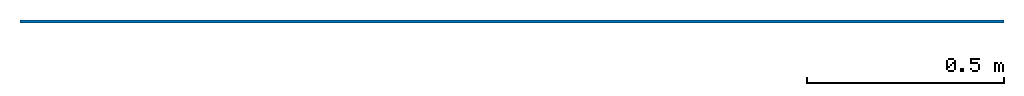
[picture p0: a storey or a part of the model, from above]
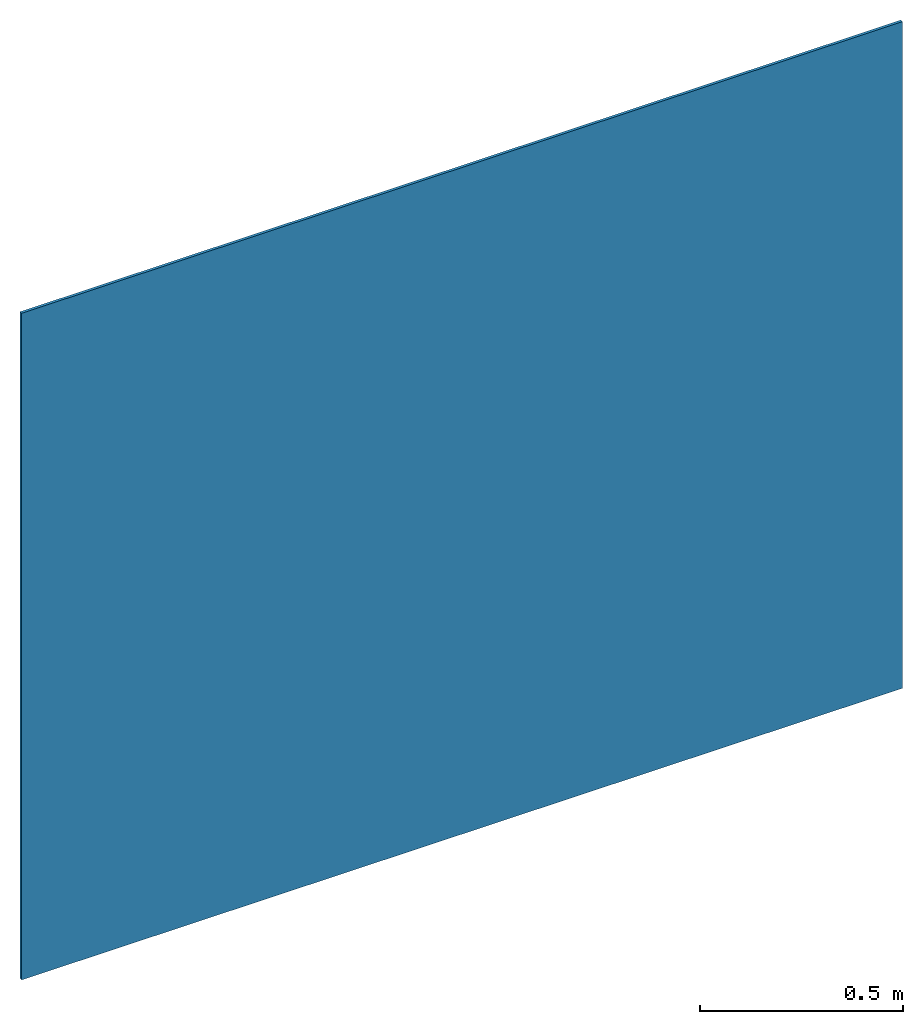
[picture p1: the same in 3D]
Properties of the parts of a building model (IFC2X3)

# File
Description: ViewDefinition[CoordinationView]
Time: 2018-09-06T15:48:25
Author: NBS
Written by: Xbim.Ifc File Processor version 2.4.1.0
Made in: Xbim version 2.4.1.0
Authorization: Add company name here

# IfcWallStandardCase: NBS_DeltaMembranes_HighDensityPolyethyleneStuddedSheets_Delta-SystemMS500
In: Default building
Type - PredefinedType: STANDARD; Material: NBS_DeltaMembranes_HighDensityPolyethyleneStuddedSheets_Delta-SystemMS500 8 mm
Type - xbim_MaterialFunctionAssignment - MaterialFunctionAssignment: 0: Substrate
Type - COBie - AccessibilityPerformance: n/a; AssetType: n/a; Category: Pr_25_57_51_74:Rubber studded sheets; CodePerformance: BBA certificate 00/3742; Color: Brown, yellow, clear; Constituents: n/a; Description: Cavity drainage membrane for use on walls and floors, as a waterproof system; DurationUnit: year; ExpectedLife: n/a; Features: n/a; Grade: n/a; Manufacturer: info@deltamembranes.com; ModelNumber: n/a; ModelReference: DELTA®-MS 500; Name: HighDensityPolyethyleneStuddedSheets_Delta-SystemMS500_DeltaMembranes; NominalHeight: 8 mm; NominalLength: 20000 mm; NominalWidth: 0 mm; ReplacementCost: n/a; Shape: n/a; Size: n/a; SustainabilityPerformance: n/a; WarrantyDescription: n/a; WarrantyDurationLabor: n/a; WarrantyDurationParts: n/a; WarrantyDurationUnit: year; WarrantyGuarantorLabor: n/a; WarrantyGuarantorParts: info@deltamembranes.com
Type - Pset_CoveringCommon - AcousticRating: n/a; Combustible: no; Finish: n/a; FireRating: Class E; FlammabilityRating: n/a; FragilityRating: n/a; Material: High density polyethylene; Reference: n/a; SurfaceSpreadOfFlame: n/a; TotalThickness: 8 mm
Type - NBS_Data - AirGap: 5.3 L/m²; Certification: n/a; ChemicalProperties: Resistant to chemicals, resistant to root penetration, rotproof, neutral towards drinking water; CompressiveStrength: >250 kN/m²; DrainageCapacity: 2.25 L/s per metre, 135 L/m per metre, 8100 L/h per metre; Elasticity: n/a; EnvironmentalProductDeclaration: n/a; IntegralPlasterKey: n/a; LateralWaterPermeability: n/a; RollSize: 2.4 x 20 m, 2 x 20 m; ServiceTemperature: -30 to +80°C; SheetThickness: 0.6 mm; SofteningTemperature: n/a; StudHeight: 8 mm; VerticalWaterPermeability: n/a; WaterStorageCapacity: n/a; Weight: n/a
Type - NBS_General - Author: NBS; BIMObjectName: NBS_DeltaMembranes_HighDensityPolyethyleneStuddedSheets_Delta-SystemMS500; ManufacturerName: Delta Membrane Systems Ltd; ManufacturerURL: www.deltamembranes.com/​; NBSCertification: www.nationalbimlibrary.com/cert/cy5zc33y; NBSDescription: High density polyethylene (PE-HD) studded sheets; NBSNote: n/a; NBSOfficeMasterTag: n/a; NBSReference: 45-65-50/354; NBSTypeID: n/a; ProductInformation: www.deltamembranes.com/​pdf/​DELTA%20System%20500%20brochure%202011.pdf; Revision: n/a; Uniclass2015Code: Rubber studded sheets; Uniclass2015Title: Pr_25_57_51_74; Uniclass2015Version: Products v1.8; Version: 9
Type - IFC - IfcExportAs: IfcCoveringType; IfcExportType: MEMBRANE
COBie - AssetIdentifier: n/a; BarCode: n/a; InstallationDate: 12/31/1900 11:59:59 PM; SerialNumber: n/a; TagNumber: n/a; WarrantyStartDate: 12/31/1900 11:59:59 PM
